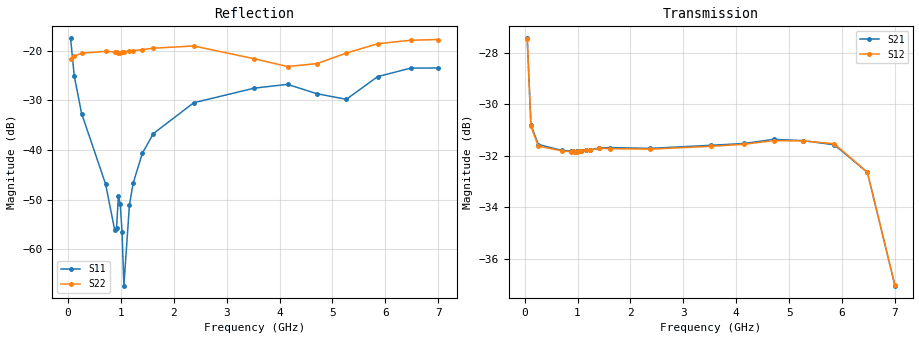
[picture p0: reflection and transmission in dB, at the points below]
! Integrated Device Technology
! Corporate Headquarters
! 6024 Silver Creek Valley Road
! San Jose, CA 95138  USA
! Phone:  1-408-284-8200
! Toll Free:  1-800-223-1366
! Webpage:  http://www.idt.com/
! Timing and RF Division
! 515 Groton Road, Suite 102
! Westford, MA 01886-6024
! Device:  F2258
! Description: Voltage Variable RF Attenuator
! Frequency:  50.0 -  6000.00 MHz
! Package:  3x3 mm Thin QFN Plastic Package: 16 pin
! Ports:  2 RF, 2 DC
!  Pin  1  = NC
!  Pin  2  = NC
!  Pin  3  = RF2  = Port 2
!  Pin  4  = GND
!  Pin  5  = Vdd
!  Pin  6  = NC
!  Pin  7  = VCTRL
!  Pin  8  = NC
!  Pin  9  = GND
!  Pin 10  = RF1  = Port 1
!  Pin 11  = NC
!  Pin 12  = NC
!  Pin 13  = NC
!  Pin 14  = NC
!  Pin 15  = NC
!  Pin 16  = NC
! Vcntrl:  1.730 Volts
! Vdd:  +3.300 Volts
! Current:  1.157 mA
! Data:  The device was measured on a the F2258 evaluation board which has
!  individual transmission lines to the RF pins.  Data was collected
!  using a calibrated network analyzer.  The evaluation board was
!  de-embedded using a TRL calibration technique.
!  The reference plane is the edge of the package pin.
! Misc:  SN 10
!  Action Tracker AT0285
! Date Measured:  2014-12-10
! Date:  2016-01-13  MJV
! Note:
!  Integrated Device Technology supplies this data as a sample of measured
!  data at the package pin for this product.  Your particular data for this
!  product may vary.
!  Data was taken at 25 degrees C.
!  Integrated Device Technology reserves the right to change this data at anytime.
!Freq_(GHz)  S11M_(dB)  S11P_(deg)  S21M_(dB)  S21P_(deg)  S12M_(dB)  S12P_(deg)  S22M_(dB)  S22P_(deg)
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# GHz S dB R 50
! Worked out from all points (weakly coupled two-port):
!   201 points, 50 MHz to 7 GHz, reference 50 ohm
!   highest |S21| = -27.45 dB at 50 MHz (marker M1); lowest = -37.1 dB at 7 GHz (marker M2)
!   lowest |S11| = -67.3 dB at 1.058 GHz (marker M3), VSWR 1.00, Z = 50 + j0.0264 ohm
!   |S11| at or under -10 dB: start of sweep to end of sweep
!   |S22| runs from -23.5 to -17.7 dB; largest |S21 - S12| = 0.00025
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0.05  -17.52 -110.3  -27.45 -55.0  -27.48 -55.1  -21.76 -64.8
0.1195  -25.10 -105.8  -30.80 -29.1  -30.86 -29.2  -21.12 -20.2
0.2585  -32.66 -109.6  -31.57 -15.7  -31.63 -15.7  -20.50 -9.5
0.71025  -46.80 -127.6  -31.80 -10.2  -31.82 -10.2  -20.14 -7.7
0.884  -56.10 167.5  -31.83 -10.3  -31.85 -10.3  -20.25 -9.6
0.91875  -55.80 143.2  -31.82 -10.4  -31.84 -10.4  -20.23 -10.0
0.9535  -49.21 -154.0  -31.85 -10.4  -31.86 -10.4  -20.53 -9.1
0.98825  -50.88 -167.2  -31.84 -10.5  -31.85 -10.5  -20.49 -9.9
1.023  -56.48 -179.2  -31.82 -10.6  -31.82 -10.6  -20.34 -10.3
1.05775  -67.32 142.2  -31.81 -10.7  -31.81 -10.7  -20.26 -10.3
1.162  -51.14 50.6  -31.77 -11.0  -31.79 -11.0  -20.09 -11.2
1.2315  -46.72 35.8  -31.78 -11.4  -31.79 -11.3  -20.01 -11.8
1.40525  -40.69 29.1  -31.71 -12.5  -31.72 -12.5  -19.78 -12.7
1.61375  -36.70 29.8  -31.69 -14.1  -31.73 -14.0  -19.50 -14.7
2.37825  -30.48 46.4  -31.72 -19.5  -31.75 -19.4  -19.05 -19.4
3.525  -27.54 90.8  -31.60 -28.4  -31.64 -28.3  -21.63 -30.0
4.1505  -26.78 104.6  -31.53 -33.8  -31.56 -33.7  -23.19 -44.6
4.7065  -28.67 95.1  -31.37 -39.1  -31.42 -39.0  -22.60 -53.6
5.2625  -29.79 53.0  -31.42 -45.2  -31.43 -45.2  -20.49 -56.2
5.85325  -25.23 29.0  -31.58 -54.4  -31.54 -54.4  -18.60 -55.8
6.47875  -23.51 40.8  -32.65 -68.4  -32.65 -68.4  -17.90 -73.2
7  -23.48 84.1  -37.05 -68.9  -37.03 -68.7  -17.75 -123.9
